VERSION 5.7 ;
  NOWIREEXTENSIONATPIN ON ;
  DIVIDERCHAR "/" ;
  BUSBITCHARS "[]" ;
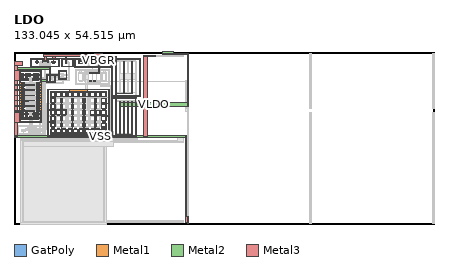
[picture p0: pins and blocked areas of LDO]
MACRO LDO
  CLASS BLOCK ;
  FOREIGN LDO ;
  ORIGIN -42.590 44.835 ;
  SIZE 133.045 BY 54.515 ;
  PIN VSS
    USE GROUND ;
    PORT
      LAYER GatPoly ;
        RECT 85.415 8.180 87.415 8.610 ;
        RECT 45.270 2.450 45.450 2.530 ;
        RECT 45.040 2.150 45.450 2.450 ;
        RECT 45.270 2.080 45.450 2.150 ;
        RECT 45.750 2.080 45.930 2.530 ;
        RECT 46.370 2.450 46.550 2.530 ;
        RECT 46.140 2.150 46.550 2.450 ;
        RECT 46.370 2.080 46.550 2.150 ;
        RECT 46.850 2.080 47.030 2.530 ;
        RECT 47.470 2.450 47.650 2.530 ;
        RECT 47.240 2.150 47.650 2.450 ;
        RECT 47.470 2.080 47.650 2.150 ;
        RECT 47.950 2.080 48.130 2.530 ;
        RECT 48.570 2.080 48.750 2.530 ;
        RECT 49.050 2.450 49.230 2.530 ;
        RECT 49.050 2.150 49.460 2.450 ;
        RECT 49.050 2.080 49.230 2.150 ;
        RECT 49.670 2.080 49.850 2.530 ;
        RECT 50.150 2.450 50.330 2.530 ;
        RECT 50.150 2.150 50.560 2.450 ;
        RECT 50.150 2.080 50.330 2.150 ;
        RECT 45.270 1.110 45.450 1.190 ;
        RECT 45.040 0.810 45.450 1.110 ;
        RECT 45.270 0.740 45.450 0.810 ;
        RECT 45.750 0.740 45.930 1.190 ;
        RECT 46.370 1.110 46.550 1.190 ;
        RECT 46.140 0.810 46.550 1.110 ;
        RECT 46.370 0.740 46.550 0.810 ;
        RECT 46.850 0.740 47.030 1.190 ;
        RECT 48.570 0.740 48.750 1.190 ;
        RECT 49.050 1.110 49.230 1.190 ;
        RECT 49.050 0.810 49.460 1.110 ;
        RECT 49.050 0.740 49.230 0.810 ;
        RECT 49.670 0.740 49.850 1.190 ;
        RECT 50.150 1.110 50.330 1.190 ;
        RECT 50.150 0.810 50.560 1.110 ;
        RECT 50.150 0.740 50.330 0.810 ;
        RECT 45.270 -0.220 45.450 -0.150 ;
        RECT 45.040 -0.520 45.450 -0.220 ;
        RECT 45.270 -0.600 45.450 -0.520 ;
        RECT 45.750 -0.600 45.930 -0.150 ;
        RECT 49.670 -0.600 49.850 -0.150 ;
        RECT 50.150 -0.220 50.330 -0.150 ;
        RECT 50.150 -0.520 50.560 -0.220 ;
        RECT 50.150 -0.600 50.330 -0.520 ;
        RECT 45.270 -1.050 45.450 -0.980 ;
        RECT 45.040 -1.350 45.450 -1.050 ;
        RECT 45.270 -1.430 45.450 -1.350 ;
        RECT 45.750 -1.430 45.930 -0.980 ;
        RECT 49.670 -1.430 49.850 -0.980 ;
        RECT 50.150 -1.050 50.330 -0.980 ;
        RECT 50.150 -1.350 50.560 -1.050 ;
        RECT 50.150 -1.430 50.330 -1.350 ;
        RECT 45.270 -1.885 45.450 -1.810 ;
        RECT 45.040 -2.185 45.450 -1.885 ;
        RECT 45.270 -2.260 45.450 -2.185 ;
        RECT 45.750 -2.260 45.930 -1.810 ;
        RECT 49.670 -2.260 49.850 -1.810 ;
        RECT 50.150 -1.885 50.330 -1.810 ;
        RECT 50.150 -2.185 50.560 -1.885 ;
        RECT 50.150 -2.260 50.330 -2.185 ;
        RECT 45.270 -2.720 45.450 -2.640 ;
        RECT 45.040 -3.020 45.450 -2.720 ;
        RECT 45.270 -3.090 45.450 -3.020 ;
        RECT 45.750 -3.090 45.930 -2.640 ;
        RECT 49.670 -3.090 49.850 -2.640 ;
        RECT 50.150 -2.720 50.330 -2.640 ;
        RECT 50.150 -3.020 50.560 -2.720 ;
        RECT 50.150 -3.090 50.330 -3.020 ;
        RECT 54.585 -3.040 55.225 -2.810 ;
        RECT 56.375 -3.040 57.015 -2.810 ;
        RECT 58.185 -3.040 58.825 -2.810 ;
        RECT 59.975 -3.040 60.615 -2.810 ;
        RECT 61.755 -3.040 62.395 -2.810 ;
        RECT 63.545 -3.040 64.185 -2.810 ;
        RECT 65.355 -3.040 65.995 -2.810 ;
        RECT 67.145 -3.040 67.785 -2.810 ;
        RECT 68.905 -3.040 69.545 -2.810 ;
        RECT 70.695 -3.040 71.335 -2.810 ;
        RECT 54.460 -3.220 55.360 -3.040 ;
        RECT 56.250 -3.220 57.150 -3.040 ;
        RECT 58.040 -3.220 58.940 -3.040 ;
        RECT 59.830 -3.220 60.730 -3.040 ;
        RECT 61.620 -3.220 62.520 -3.040 ;
        RECT 63.410 -3.220 64.310 -3.040 ;
        RECT 65.200 -3.220 66.100 -3.040 ;
        RECT 66.990 -3.220 67.890 -3.040 ;
        RECT 68.780 -3.220 69.680 -3.040 ;
        RECT 70.570 -3.220 71.470 -3.040 ;
        RECT 45.270 -3.550 45.450 -3.470 ;
        RECT 45.040 -3.850 45.450 -3.550 ;
        RECT 45.270 -3.920 45.450 -3.850 ;
        RECT 45.750 -3.920 45.930 -3.470 ;
        RECT 49.670 -3.920 49.850 -3.470 ;
        RECT 50.150 -3.550 50.330 -3.470 ;
        RECT 50.150 -3.850 50.560 -3.550 ;
        RECT 50.150 -3.920 50.330 -3.850 ;
        RECT 45.270 -4.385 45.450 -4.300 ;
        RECT 45.040 -4.685 45.450 -4.385 ;
        RECT 45.270 -4.750 45.450 -4.685 ;
        RECT 45.750 -4.750 45.930 -4.300 ;
        RECT 49.670 -4.750 49.850 -4.300 ;
        RECT 50.150 -4.385 50.330 -4.300 ;
        RECT 50.150 -4.685 50.560 -4.385 ;
        RECT 50.150 -4.750 50.330 -4.685 ;
        RECT 45.270 -5.215 45.450 -5.130 ;
        RECT 45.040 -5.515 45.450 -5.215 ;
        RECT 45.270 -5.580 45.450 -5.515 ;
        RECT 45.750 -5.580 45.930 -5.130 ;
        RECT 49.670 -5.580 49.850 -5.130 ;
        RECT 50.150 -5.215 50.330 -5.130 ;
        RECT 54.460 -5.150 55.360 -4.420 ;
        RECT 56.250 -4.600 57.150 -4.420 ;
        RECT 58.040 -4.600 58.940 -4.420 ;
        RECT 59.830 -4.600 60.730 -4.420 ;
        RECT 61.620 -4.600 62.520 -4.420 ;
        RECT 63.410 -4.600 64.310 -4.420 ;
        RECT 65.200 -4.600 66.100 -4.420 ;
        RECT 66.990 -4.600 67.890 -4.420 ;
        RECT 68.780 -4.600 69.680 -4.420 ;
        RECT 70.570 -4.600 71.470 -4.420 ;
        RECT 70.570 -5.150 71.470 -4.970 ;
        RECT 50.150 -5.515 50.560 -5.215 ;
        RECT 50.150 -5.580 50.330 -5.515 ;
        RECT 45.270 -6.030 45.450 -5.960 ;
        RECT 45.040 -6.330 45.450 -6.030 ;
        RECT 45.270 -6.410 45.450 -6.330 ;
        RECT 45.750 -6.410 45.930 -5.960 ;
        RECT 49.670 -6.410 49.850 -5.960 ;
        RECT 50.150 -6.030 50.330 -5.960 ;
        RECT 50.150 -6.330 50.560 -6.030 ;
        RECT 50.150 -6.410 50.330 -6.330 ;
        RECT 54.460 -6.530 55.360 -6.350 ;
        RECT 45.270 -6.860 45.450 -6.790 ;
        RECT 45.040 -7.160 45.450 -6.860 ;
        RECT 45.270 -7.240 45.450 -7.160 ;
        RECT 45.750 -7.240 45.930 -6.790 ;
        RECT 49.670 -7.240 49.850 -6.790 ;
        RECT 50.150 -6.860 50.330 -6.790 ;
        RECT 50.150 -7.160 50.560 -6.860 ;
        RECT 54.460 -7.080 55.360 -6.900 ;
        RECT 70.570 -7.080 71.470 -6.350 ;
        RECT 50.150 -7.240 50.330 -7.160 ;
        RECT 45.270 -7.695 45.450 -7.620 ;
        RECT 45.040 -7.995 45.450 -7.695 ;
        RECT 45.270 -8.070 45.450 -7.995 ;
        RECT 45.750 -8.070 45.930 -7.620 ;
        RECT 49.670 -8.070 49.850 -7.620 ;
        RECT 50.150 -7.695 50.330 -7.620 ;
        RECT 50.150 -7.995 50.560 -7.695 ;
        RECT 50.150 -8.070 50.330 -7.995 ;
        RECT 45.270 -8.525 45.450 -8.450 ;
        RECT 45.040 -8.825 45.450 -8.525 ;
        RECT 45.270 -8.900 45.450 -8.825 ;
        RECT 45.750 -8.900 45.930 -8.450 ;
        RECT 49.670 -8.900 49.850 -8.450 ;
        RECT 50.150 -8.525 50.330 -8.450 ;
        RECT 50.150 -8.825 50.560 -8.525 ;
        RECT 50.150 -8.900 50.330 -8.825 ;
        RECT 54.460 -9.010 55.360 -8.280 ;
        RECT 70.570 -8.460 71.470 -8.280 ;
        RECT 56.385 -8.830 57.025 -8.640 ;
        RECT 58.170 -8.830 58.810 -8.640 ;
        RECT 56.250 -9.010 57.150 -8.830 ;
        RECT 58.040 -9.010 58.940 -8.830 ;
        RECT 66.990 -9.010 67.890 -8.830 ;
        RECT 68.780 -9.010 69.680 -8.830 ;
        RECT 70.570 -9.010 71.470 -8.830 ;
        RECT 45.270 -9.865 45.450 -9.790 ;
        RECT 45.040 -10.165 45.450 -9.865 ;
        RECT 45.270 -10.240 45.450 -10.165 ;
        RECT 45.750 -10.240 45.930 -9.790 ;
        RECT 46.370 -9.870 46.550 -9.790 ;
        RECT 46.140 -10.170 46.550 -9.870 ;
        RECT 46.370 -10.240 46.550 -10.170 ;
        RECT 46.850 -10.240 47.030 -9.790 ;
        RECT 48.570 -10.240 48.750 -9.790 ;
        RECT 49.050 -9.870 49.230 -9.790 ;
        RECT 49.050 -10.170 49.460 -9.870 ;
        RECT 49.050 -10.240 49.230 -10.170 ;
        RECT 49.670 -10.240 49.850 -9.790 ;
        RECT 50.150 -9.865 50.330 -9.790 ;
        RECT 50.150 -10.165 50.560 -9.865 ;
        RECT 50.150 -10.240 50.330 -10.165 ;
        RECT 54.460 -10.390 55.360 -10.210 ;
        RECT 56.250 -10.390 57.150 -10.210 ;
        RECT 58.040 -10.390 58.940 -10.210 ;
        RECT 66.990 -10.390 67.890 -10.210 ;
        RECT 68.780 -10.390 69.680 -10.210 ;
        RECT 67.120 -10.580 67.760 -10.390 ;
        RECT 68.905 -10.580 69.545 -10.390 ;
        RECT 54.460 -10.940 55.360 -10.760 ;
        RECT 70.570 -10.940 71.470 -10.210 ;
        RECT 45.270 -11.210 45.450 -11.130 ;
        RECT 45.040 -11.510 45.450 -11.210 ;
        RECT 45.270 -11.580 45.450 -11.510 ;
        RECT 45.750 -11.580 45.930 -11.130 ;
        RECT 46.370 -11.210 46.550 -11.130 ;
        RECT 46.140 -11.510 46.550 -11.210 ;
        RECT 46.370 -11.580 46.550 -11.510 ;
        RECT 46.850 -11.580 47.030 -11.130 ;
        RECT 47.470 -11.580 47.650 -11.130 ;
        RECT 47.950 -11.210 48.130 -11.130 ;
        RECT 47.950 -11.510 48.360 -11.210 ;
        RECT 47.950 -11.580 48.130 -11.510 ;
        RECT 48.570 -11.580 48.750 -11.130 ;
        RECT 49.050 -11.210 49.230 -11.130 ;
        RECT 49.050 -11.510 49.460 -11.210 ;
        RECT 49.050 -11.580 49.230 -11.510 ;
        RECT 49.670 -11.580 49.850 -11.130 ;
        RECT 50.150 -11.205 50.330 -11.130 ;
        RECT 50.150 -11.505 50.560 -11.205 ;
        RECT 50.150 -11.580 50.330 -11.505 ;
        RECT 54.460 -12.870 55.360 -12.140 ;
        RECT 70.570 -12.320 71.470 -12.140 ;
        RECT 70.570 -12.870 71.470 -12.690 ;
        RECT 54.460 -14.250 55.360 -14.070 ;
        RECT 54.460 -14.800 55.360 -14.620 ;
        RECT 56.250 -14.800 57.150 -14.620 ;
        RECT 58.040 -14.800 58.940 -14.620 ;
        RECT 59.830 -14.800 60.730 -14.620 ;
        RECT 61.620 -14.800 62.520 -14.620 ;
        RECT 63.410 -14.800 64.310 -14.620 ;
        RECT 65.200 -14.800 66.100 -14.620 ;
        RECT 66.990 -14.800 67.890 -14.620 ;
        RECT 68.780 -14.800 69.680 -14.620 ;
        RECT 70.570 -14.800 71.470 -14.070 ;
        RECT 54.460 -16.180 55.360 -16.000 ;
        RECT 56.250 -16.180 57.150 -16.000 ;
        RECT 58.040 -16.180 58.940 -16.000 ;
        RECT 59.830 -16.180 60.730 -16.000 ;
        RECT 61.620 -16.180 62.520 -16.000 ;
        RECT 63.410 -16.180 64.310 -16.000 ;
        RECT 65.200 -16.180 66.100 -16.000 ;
        RECT 66.990 -16.180 67.890 -16.000 ;
        RECT 68.780 -16.180 69.680 -16.000 ;
        RECT 70.570 -16.180 71.470 -16.000 ;
        RECT 54.585 -16.410 55.225 -16.180 ;
        RECT 56.375 -16.410 57.015 -16.180 ;
        RECT 58.185 -16.410 58.825 -16.180 ;
        RECT 59.975 -16.410 60.615 -16.180 ;
        RECT 61.755 -16.410 62.395 -16.180 ;
        RECT 63.545 -16.410 64.185 -16.180 ;
        RECT 65.355 -16.410 65.995 -16.180 ;
        RECT 67.145 -16.410 67.785 -16.180 ;
        RECT 68.905 -16.410 69.545 -16.180 ;
        RECT 70.695 -16.410 71.335 -16.180 ;
        RECT 97.595 -44.525 98.025 -42.525 ;
      LAYER Metal1 ;
        RECT 83.660 8.310 87.395 8.610 ;
        RECT 44.350 3.425 51.250 3.725 ;
        RECT 44.350 2.430 44.650 3.425 ;
        RECT 45.110 2.640 45.750 2.800 ;
        RECT 46.210 2.640 46.850 2.800 ;
        RECT 47.310 2.640 47.950 2.800 ;
        RECT 48.750 2.640 49.390 2.800 ;
        RECT 49.850 2.640 50.490 2.800 ;
        RECT 45.110 2.430 45.270 2.640 ;
        RECT 46.210 2.430 46.370 2.640 ;
        RECT 47.310 2.430 47.470 2.640 ;
        RECT 44.350 2.170 47.470 2.430 ;
        RECT 44.350 1.090 44.650 2.170 ;
        RECT 45.110 1.970 45.270 2.170 ;
        RECT 46.210 1.970 46.370 2.170 ;
        RECT 47.310 1.970 47.470 2.170 ;
        RECT 49.230 2.430 49.390 2.640 ;
        RECT 50.330 2.430 50.490 2.640 ;
        RECT 50.950 2.430 51.250 3.425 ;
        RECT 56.730 3.420 59.370 3.720 ;
        RECT 49.230 2.170 51.250 2.430 ;
        RECT 49.230 1.970 49.390 2.170 ;
        RECT 50.330 1.970 50.490 2.170 ;
        RECT 45.110 1.810 45.750 1.970 ;
        RECT 46.210 1.810 46.850 1.970 ;
        RECT 47.310 1.810 47.950 1.970 ;
        RECT 48.750 1.810 49.390 1.970 ;
        RECT 49.850 1.810 50.490 1.970 ;
        RECT 45.110 1.300 45.750 1.460 ;
        RECT 46.210 1.300 46.850 1.460 ;
        RECT 48.750 1.300 49.390 1.460 ;
        RECT 49.850 1.300 50.490 1.460 ;
        RECT 45.110 1.090 45.270 1.300 ;
        RECT 46.210 1.090 46.370 1.300 ;
        RECT 44.350 0.830 46.370 1.090 ;
        RECT 44.350 0.120 44.650 0.830 ;
        RECT 45.110 0.630 45.270 0.830 ;
        RECT 46.210 0.630 46.370 0.830 ;
        RECT 49.230 1.090 49.390 1.300 ;
        RECT 50.330 1.090 50.490 1.300 ;
        RECT 50.950 1.090 51.250 2.170 ;
        RECT 49.230 0.830 51.250 1.090 ;
        RECT 49.230 0.630 49.390 0.830 ;
        RECT 50.330 0.630 50.490 0.830 ;
        RECT 45.110 0.470 45.750 0.630 ;
        RECT 46.210 0.470 46.850 0.630 ;
        RECT 48.750 0.470 49.390 0.630 ;
        RECT 49.850 0.470 50.490 0.630 ;
        RECT 50.950 0.120 51.250 0.830 ;
        RECT 44.350 -0.040 45.750 0.120 ;
        RECT 49.850 -0.040 51.250 0.120 ;
        RECT 52.960 2.275 55.810 2.575 ;
        RECT 52.960 0.375 53.260 2.275 ;
        RECT 53.890 1.470 54.050 1.475 ;
        RECT 53.840 0.770 54.050 1.470 ;
        RECT 55.510 0.375 55.810 2.275 ;
        RECT 56.730 1.180 57.030 3.420 ;
        RECT 59.070 1.180 59.370 3.420 ;
        RECT 56.730 0.880 59.370 1.180 ;
        RECT 52.960 0.075 55.810 0.375 ;
        RECT 44.350 -0.710 45.270 -0.040 ;
        RECT 46.350 -0.710 47.050 -0.680 ;
        RECT 50.330 -0.710 51.250 -0.040 ;
        RECT 44.350 -0.870 45.750 -0.710 ;
        RECT 46.350 -0.870 49.050 -0.710 ;
        RECT 49.850 -0.870 51.250 -0.710 ;
        RECT 44.350 -1.540 45.270 -0.870 ;
        RECT 46.350 -0.890 47.050 -0.870 ;
        RECT 50.330 -1.540 51.250 -0.870 ;
        RECT 44.350 -1.700 45.750 -1.540 ;
        RECT 49.850 -1.700 51.250 -1.540 ;
        RECT 44.350 -2.370 45.270 -1.700 ;
        RECT 46.350 -2.370 47.050 -2.345 ;
        RECT 50.330 -2.370 51.250 -1.700 ;
        RECT 44.350 -2.530 45.750 -2.370 ;
        RECT 46.350 -2.530 49.050 -2.370 ;
        RECT 49.850 -2.530 51.250 -2.370 ;
        RECT 44.350 -3.200 45.270 -2.530 ;
        RECT 46.350 -2.555 47.050 -2.530 ;
        RECT 50.330 -3.200 51.250 -2.530 ;
        RECT 44.350 -3.360 45.750 -3.200 ;
        RECT 49.850 -3.360 51.250 -3.200 ;
        RECT 44.350 -4.030 45.270 -3.360 ;
        RECT 46.350 -4.030 47.050 -4.005 ;
        RECT 50.330 -4.030 51.250 -3.360 ;
        RECT 44.350 -4.190 45.750 -4.030 ;
        RECT 46.350 -4.190 49.050 -4.030 ;
        RECT 49.850 -4.190 51.250 -4.030 ;
        RECT 44.350 -4.860 45.270 -4.190 ;
        RECT 46.350 -4.215 47.050 -4.190 ;
        RECT 50.330 -4.860 51.250 -4.190 ;
        RECT 44.350 -5.020 45.750 -4.860 ;
        RECT 49.850 -5.020 51.250 -4.860 ;
        RECT 44.350 -5.690 45.270 -5.020 ;
        RECT 46.350 -5.690 47.050 -5.665 ;
        RECT 50.330 -5.690 51.250 -5.020 ;
        RECT 44.350 -5.850 45.750 -5.690 ;
        RECT 46.350 -5.850 49.050 -5.690 ;
        RECT 49.850 -5.850 51.250 -5.690 ;
        RECT 44.350 -6.520 45.270 -5.850 ;
        RECT 46.350 -5.875 47.050 -5.850 ;
        RECT 50.330 -6.520 51.250 -5.850 ;
        RECT 44.350 -6.680 45.750 -6.520 ;
        RECT 49.850 -6.680 51.250 -6.520 ;
        RECT 44.350 -7.350 45.270 -6.680 ;
        RECT 46.350 -7.350 47.050 -7.325 ;
        RECT 50.330 -7.350 51.250 -6.680 ;
        RECT 44.350 -7.510 45.750 -7.350 ;
        RECT 46.350 -7.510 49.050 -7.350 ;
        RECT 49.850 -7.510 51.250 -7.350 ;
        RECT 44.350 -8.180 45.270 -7.510 ;
        RECT 46.350 -7.535 47.050 -7.510 ;
        RECT 50.330 -8.180 51.250 -7.510 ;
        RECT 44.350 -8.340 45.750 -8.180 ;
        RECT 49.850 -8.340 51.250 -8.180 ;
        RECT 44.350 -9.010 45.270 -8.340 ;
        RECT 46.345 -9.010 47.045 -8.985 ;
        RECT 50.330 -9.010 51.250 -8.340 ;
        RECT 44.350 -9.170 45.750 -9.010 ;
        RECT 46.345 -9.170 49.050 -9.010 ;
        RECT 49.850 -9.170 51.250 -9.010 ;
        RECT 44.350 -9.885 44.650 -9.170 ;
        RECT 46.345 -9.195 47.045 -9.170 ;
        RECT 45.110 -9.680 45.750 -9.520 ;
        RECT 46.210 -9.680 46.850 -9.520 ;
        RECT 48.750 -9.680 49.390 -9.520 ;
        RECT 49.850 -9.680 50.490 -9.520 ;
        RECT 45.110 -9.885 45.270 -9.680 ;
        RECT 44.350 -9.890 45.270 -9.885 ;
        RECT 46.210 -9.890 46.370 -9.680 ;
        RECT 44.350 -10.145 46.370 -9.890 ;
        RECT 44.350 -11.230 44.650 -10.145 ;
        RECT 45.110 -10.150 46.370 -10.145 ;
        RECT 45.110 -10.350 45.270 -10.150 ;
        RECT 46.210 -10.350 46.370 -10.150 ;
        RECT 49.230 -9.890 49.390 -9.680 ;
        RECT 50.330 -9.890 50.490 -9.680 ;
        RECT 50.950 -9.890 51.250 -9.170 ;
        RECT 49.230 -10.150 51.250 -9.890 ;
        RECT 49.230 -10.350 49.390 -10.150 ;
        RECT 50.330 -10.350 50.490 -10.150 ;
        RECT 45.110 -10.510 45.750 -10.350 ;
        RECT 46.210 -10.510 46.850 -10.350 ;
        RECT 48.750 -10.510 49.390 -10.350 ;
        RECT 49.850 -10.510 50.490 -10.350 ;
        RECT 45.110 -11.020 45.750 -10.860 ;
        RECT 46.210 -11.020 46.850 -10.860 ;
        RECT 47.650 -11.020 48.290 -10.860 ;
        RECT 48.750 -11.020 49.390 -10.860 ;
        RECT 49.850 -11.020 50.490 -10.860 ;
        RECT 45.110 -11.230 45.270 -11.020 ;
        RECT 46.210 -11.230 46.370 -11.020 ;
        RECT 44.350 -11.490 46.370 -11.230 ;
        RECT 44.350 -12.475 44.650 -11.490 ;
        RECT 45.110 -11.690 45.270 -11.490 ;
        RECT 46.210 -11.690 46.370 -11.490 ;
        RECT 48.130 -11.230 48.290 -11.020 ;
        RECT 49.230 -11.230 49.390 -11.020 ;
        RECT 50.330 -11.230 50.490 -11.020 ;
        RECT 50.950 -11.230 51.250 -10.150 ;
        RECT 48.130 -11.490 51.250 -11.230 ;
        RECT 48.130 -11.690 48.290 -11.490 ;
        RECT 49.230 -11.690 49.390 -11.490 ;
        RECT 50.330 -11.690 50.490 -11.490 ;
        RECT 45.110 -11.850 45.750 -11.690 ;
        RECT 46.210 -11.850 46.850 -11.690 ;
        RECT 47.650 -11.850 48.290 -11.690 ;
        RECT 48.750 -11.850 49.390 -11.690 ;
        RECT 49.850 -11.850 50.490 -11.690 ;
        RECT 50.950 -12.475 51.250 -11.490 ;
        RECT 44.350 -12.775 51.250 -12.475 ;
        RECT 53.215 -2.385 72.715 -2.085 ;
        RECT 53.215 -8.565 53.515 -2.385 ;
        RECT 60.045 -2.880 65.975 -2.385 ;
        RECT 54.190 -3.040 71.740 -2.880 ;
        RECT 54.190 -4.705 54.350 -3.040 ;
        RECT 55.470 -4.705 55.630 -3.040 ;
        RECT 55.980 -4.420 56.140 -3.040 ;
        RECT 57.260 -4.420 57.420 -3.040 ;
        RECT 57.770 -4.420 57.930 -3.040 ;
        RECT 59.050 -4.420 59.210 -3.040 ;
        RECT 59.560 -4.420 59.720 -3.040 ;
        RECT 60.840 -4.420 61.000 -3.040 ;
        RECT 61.350 -4.420 61.510 -3.040 ;
        RECT 62.630 -4.420 62.790 -3.040 ;
        RECT 63.140 -4.420 63.300 -3.040 ;
        RECT 64.420 -4.420 64.580 -3.040 ;
        RECT 64.930 -4.420 65.090 -3.040 ;
        RECT 66.210 -4.420 66.370 -3.040 ;
        RECT 66.720 -4.420 66.880 -3.040 ;
        RECT 68.000 -4.420 68.160 -3.040 ;
        RECT 68.510 -4.420 68.670 -3.040 ;
        RECT 69.790 -4.420 69.950 -3.040 ;
        RECT 70.300 -4.420 70.460 -3.040 ;
        RECT 71.580 -4.420 71.740 -3.040 ;
        RECT 54.190 -4.865 55.630 -4.705 ;
        RECT 54.190 -6.350 54.350 -4.865 ;
        RECT 55.470 -6.350 55.630 -4.865 ;
        RECT 57.260 -6.350 57.930 -5.150 ;
        RECT 60.840 -6.350 61.510 -5.150 ;
        RECT 64.420 -6.350 65.090 -5.150 ;
        RECT 68.000 -6.350 68.670 -5.150 ;
        RECT 70.300 -6.635 70.460 -5.150 ;
        RECT 71.580 -6.635 71.740 -5.150 ;
        RECT 72.415 -6.635 72.715 -2.385 ;
        RECT 70.300 -6.795 72.715 -6.635 ;
        RECT 54.190 -8.565 54.350 -7.080 ;
        RECT 55.470 -8.565 55.630 -7.080 ;
        RECT 57.260 -8.280 57.930 -7.080 ;
        RECT 60.840 -8.280 61.510 -7.080 ;
        RECT 64.420 -8.280 65.090 -7.080 ;
        RECT 68.000 -8.280 68.670 -7.080 ;
        RECT 70.300 -8.280 70.460 -6.795 ;
        RECT 71.580 -8.280 71.740 -6.795 ;
        RECT 53.215 -8.710 55.630 -8.565 ;
        RECT 53.215 -8.725 59.210 -8.710 ;
        RECT 53.215 -12.425 53.515 -8.725 ;
        RECT 54.190 -10.210 54.350 -8.725 ;
        RECT 55.470 -8.870 59.210 -8.725 ;
        RECT 55.470 -10.210 55.630 -8.870 ;
        RECT 55.980 -10.210 56.140 -8.870 ;
        RECT 57.260 -10.210 57.420 -8.870 ;
        RECT 57.770 -10.210 57.930 -8.870 ;
        RECT 59.050 -10.210 59.210 -8.870 ;
        RECT 60.840 -10.210 61.510 -9.010 ;
        RECT 64.420 -10.210 65.090 -9.010 ;
        RECT 66.720 -10.350 66.880 -9.010 ;
        RECT 68.000 -10.350 68.160 -9.010 ;
        RECT 68.510 -10.350 68.670 -9.010 ;
        RECT 69.790 -10.350 69.950 -9.010 ;
        RECT 70.300 -10.350 70.460 -9.010 ;
        RECT 66.720 -10.495 70.460 -10.350 ;
        RECT 71.580 -10.495 71.740 -9.010 ;
        RECT 72.415 -10.495 72.715 -6.795 ;
        RECT 66.720 -10.510 72.715 -10.495 ;
        RECT 70.300 -10.655 72.715 -10.510 ;
        RECT 54.190 -12.425 54.350 -10.940 ;
        RECT 55.470 -12.425 55.630 -10.940 ;
        RECT 57.260 -12.140 57.930 -10.940 ;
        RECT 60.840 -12.140 61.510 -10.940 ;
        RECT 64.420 -12.140 65.090 -10.940 ;
        RECT 68.000 -12.140 68.670 -10.940 ;
        RECT 70.300 -12.140 70.460 -10.655 ;
        RECT 71.580 -12.140 71.740 -10.655 ;
        RECT 53.215 -12.585 55.630 -12.425 ;
        RECT 53.215 -16.835 53.515 -12.585 ;
        RECT 54.190 -14.070 54.350 -12.585 ;
        RECT 55.470 -14.070 55.630 -12.585 ;
        RECT 57.260 -14.070 57.930 -12.870 ;
        RECT 60.840 -14.070 61.510 -12.870 ;
        RECT 64.420 -14.070 65.090 -12.870 ;
        RECT 68.000 -14.070 68.670 -12.870 ;
        RECT 70.300 -14.355 70.460 -12.870 ;
        RECT 71.580 -14.355 71.740 -12.870 ;
        RECT 70.300 -14.515 71.740 -14.355 ;
        RECT 54.190 -16.180 54.350 -14.800 ;
        RECT 55.470 -16.180 55.630 -14.800 ;
        RECT 55.980 -16.180 56.140 -14.800 ;
        RECT 57.260 -16.180 57.420 -14.800 ;
        RECT 57.770 -16.180 57.930 -14.800 ;
        RECT 59.050 -16.180 59.210 -14.800 ;
        RECT 59.560 -16.180 59.720 -14.800 ;
        RECT 60.840 -16.180 61.000 -14.800 ;
        RECT 61.350 -16.180 61.510 -14.800 ;
        RECT 62.630 -16.180 62.790 -14.800 ;
        RECT 63.140 -16.180 63.300 -14.800 ;
        RECT 64.420 -16.180 64.580 -14.800 ;
        RECT 64.930 -16.180 65.090 -14.800 ;
        RECT 66.210 -16.180 66.370 -14.800 ;
        RECT 66.720 -16.180 66.880 -14.800 ;
        RECT 68.000 -16.180 68.160 -14.800 ;
        RECT 68.510 -16.180 68.670 -14.800 ;
        RECT 69.790 -16.180 69.950 -14.800 ;
        RECT 70.300 -16.180 70.460 -14.515 ;
        RECT 71.580 -16.180 71.740 -14.515 ;
        RECT 54.190 -16.340 71.740 -16.180 ;
        RECT 57.245 -16.835 57.945 -16.790 ;
        RECT 60.045 -16.835 65.975 -16.340 ;
        RECT 67.985 -16.835 68.685 -16.790 ;
        RECT 72.415 -16.835 72.715 -10.655 ;
        RECT 53.215 -17.135 72.715 -16.835 ;
        RECT 57.245 -17.410 57.945 -17.135 ;
        RECT 60.825 -17.410 61.525 -17.135 ;
        RECT 64.405 -17.410 65.105 -17.135 ;
        RECT 67.985 -17.410 68.685 -17.135 ;
        RECT 97.595 -44.505 97.895 -42.545 ;
      LAYER Metal2 ;
        RECT 83.660 8.365 84.770 8.565 ;
        RECT 43.065 4.000 54.045 4.700 ;
        RECT 44.395 0.495 44.595 3.655 ;
        RECT 55.515 2.210 57.025 2.410 ;
        RECT 51.000 0.260 53.210 0.960 ;
        RECT 53.840 0.770 54.050 1.470 ;
        RECT 46.350 -0.890 47.050 -0.680 ;
        RECT 46.350 -2.555 47.050 -2.345 ;
        RECT 46.350 -4.215 47.050 -4.005 ;
        RECT 46.350 -5.875 47.050 -5.665 ;
        RECT 57.495 -6.305 57.695 -5.195 ;
        RECT 61.075 -6.305 61.275 -5.195 ;
        RECT 64.655 -6.305 64.855 -5.195 ;
        RECT 68.235 -6.305 68.435 -5.195 ;
        RECT 46.350 -7.535 47.050 -7.325 ;
        RECT 57.495 -8.230 57.695 -7.120 ;
        RECT 61.075 -8.230 61.275 -7.120 ;
        RECT 64.655 -8.230 64.855 -7.120 ;
        RECT 68.235 -8.230 68.435 -7.120 ;
        RECT 46.345 -9.195 47.045 -8.985 ;
        RECT 44.395 -12.705 44.595 -9.545 ;
        RECT 61.075 -10.175 61.275 -9.065 ;
        RECT 64.655 -10.175 64.855 -9.065 ;
        RECT 57.495 -12.105 57.695 -10.995 ;
        RECT 61.075 -12.105 61.275 -10.995 ;
        RECT 64.655 -12.105 64.855 -10.995 ;
        RECT 68.235 -12.105 68.435 -10.995 ;
        RECT 57.495 -14.010 57.695 -12.900 ;
        RECT 61.075 -14.010 61.275 -12.900 ;
        RECT 64.655 -14.010 64.855 -12.900 ;
        RECT 68.235 -14.010 68.435 -12.900 ;
        RECT 97.055 -16.795 97.255 -16.740 ;
        RECT 42.850 -17.405 97.255 -16.795 ;
        RECT 97.055 -17.440 97.255 -17.405 ;
        RECT 97.640 -44.490 97.840 -42.560 ;
      LAYER Metal3 ;
        RECT 42.590 5.390 45.300 6.740 ;
        RECT 42.590 3.655 43.545 5.390 ;
        RECT 42.590 0.495 44.595 3.655 ;
        RECT 53.845 0.770 54.045 4.700 ;
        RECT 42.590 -0.550 43.545 0.495 ;
        RECT 42.590 -1.055 47.050 -0.550 ;
        RECT 42.590 -2.350 43.545 -1.055 ;
        RECT 42.590 -2.550 47.050 -2.350 ;
        RECT 42.590 -4.010 43.545 -2.550 ;
        RECT 42.590 -4.210 47.050 -4.010 ;
        RECT 42.590 -5.670 43.545 -4.210 ;
        RECT 42.590 -5.870 47.050 -5.670 ;
        RECT 42.590 -7.330 43.545 -5.870 ;
        RECT 42.590 -7.530 47.050 -7.330 ;
        RECT 42.590 -8.990 43.545 -7.530 ;
        RECT 42.590 -9.190 47.045 -8.990 ;
        RECT 42.590 -9.545 43.545 -9.190 ;
        RECT 42.590 -12.705 44.595 -9.545 ;
        RECT 42.590 -16.795 43.545 -12.705 ;
        RECT 57.495 -16.795 57.695 -5.195 ;
        RECT 61.075 -16.795 61.275 -5.195 ;
        RECT 64.655 -16.795 64.855 -5.195 ;
        RECT 68.235 -16.795 68.435 -5.195 ;
        RECT 42.590 -17.200 43.550 -16.795 ;
        RECT 42.850 -17.405 43.550 -17.200 ;
        RECT 57.245 -17.405 57.945 -16.795 ;
        RECT 60.825 -17.405 61.525 -16.795 ;
        RECT 64.405 -17.405 65.105 -16.795 ;
        RECT 67.985 -17.405 68.685 -16.795 ;
        RECT 83.660 -17.200 84.770 8.610 ;
        RECT 97.030 -42.560 97.280 -16.740 ;
        RECT 97.030 -44.490 97.840 -42.560 ;
    END
  END VSS
  PIN VBGR
    ANTENNAGATEAREA 4.050000 ;
    PORT
      LAYER GatPoly ;
        RECT 66.485 2.940 67.125 3.170 ;
        RECT 67.770 2.940 68.410 3.170 ;
        RECT 66.360 2.760 67.260 2.940 ;
        RECT 67.640 2.760 68.540 2.940 ;
        RECT 66.360 0.330 67.260 0.510 ;
        RECT 67.640 0.330 68.540 0.510 ;
      LAYER Metal1 ;
        RECT 66.455 2.915 67.155 3.125 ;
        RECT 67.740 2.915 68.440 3.125 ;
      LAYER Metal2 ;
        RECT 66.455 2.920 69.705 3.120 ;
      LAYER Metal3 ;
        RECT 68.230 8.240 70.660 9.075 ;
        RECT 69.415 2.920 69.705 8.240 ;
    END
  END VBGR
  PIN VDD
    USE POWER ;
    PORT
      LAYER GatPoly ;
        RECT 49.725 6.560 50.025 6.790 ;
        RECT 54.945 6.560 55.245 6.790 ;
        RECT 63.435 6.665 64.075 6.965 ;
        RECT 70.855 6.665 71.495 6.965 ;
        RECT 49.675 6.380 50.075 6.560 ;
        RECT 54.895 6.380 55.295 6.560 ;
        RECT 63.300 6.485 64.200 6.665 ;
        RECT 70.720 6.485 71.620 6.665 ;
        RECT 49.675 6.050 50.075 6.230 ;
        RECT 54.895 6.050 55.295 6.230 ;
        RECT 63.300 5.855 64.200 6.035 ;
        RECT 70.720 5.855 71.620 6.035 ;
      LAYER Metal1 ;
        RECT 47.885 7.405 57.085 7.705 ;
        RECT 47.885 5.205 48.185 7.405 ;
        RECT 49.745 6.720 50.005 7.405 ;
        RECT 52.135 6.835 52.835 6.905 ;
        RECT 49.375 6.560 50.375 6.720 ;
        RECT 49.375 6.175 49.535 6.560 ;
        RECT 50.215 6.175 50.375 6.560 ;
        RECT 51.565 6.675 53.405 6.835 ;
        RECT 54.965 6.720 55.225 7.405 ;
        RECT 51.565 6.175 51.725 6.675 ;
        RECT 53.245 6.175 53.405 6.675 ;
        RECT 54.595 6.560 55.595 6.720 ;
        RECT 54.595 6.175 54.755 6.560 ;
        RECT 55.435 6.175 55.595 6.560 ;
        RECT 56.785 5.205 57.085 7.405 ;
        RECT 47.885 4.905 57.085 5.205 ;
        RECT 57.785 7.405 61.285 7.705 ;
        RECT 57.785 5.205 58.085 7.405 ;
        RECT 59.015 6.155 59.225 6.855 ;
        RECT 60.985 5.205 61.285 7.405 ;
        RECT 57.785 4.905 61.285 5.205 ;
        RECT 61.710 7.400 73.210 7.700 ;
        RECT 61.710 5.000 62.010 7.400 ;
        RECT 63.455 6.895 64.055 7.400 ;
        RECT 67.155 6.930 67.855 7.110 ;
        RECT 63.030 6.735 64.470 6.895 ;
        RECT 63.030 6.035 63.190 6.735 ;
        RECT 64.310 6.035 64.470 6.735 ;
        RECT 66.100 6.770 68.820 6.930 ;
        RECT 70.875 6.895 71.475 7.400 ;
        RECT 66.100 6.035 66.260 6.770 ;
        RECT 68.660 6.035 68.820 6.770 ;
        RECT 70.450 6.735 71.890 6.895 ;
        RECT 70.450 6.035 70.610 6.735 ;
        RECT 71.730 6.035 71.890 6.735 ;
        RECT 72.910 5.000 73.210 7.400 ;
        RECT 61.710 4.700 73.210 5.000 ;
        RECT 73.565 7.405 82.665 7.705 ;
        RECT 73.565 -3.995 73.865 7.405 ;
        RECT 74.835 5.445 74.995 6.505 ;
        RECT 74.810 3.515 75.020 5.445 ;
        RECT 74.835 -3.345 74.995 3.515 ;
        RECT 77.395 -3.345 77.555 6.505 ;
        RECT 79.955 -3.345 80.115 6.505 ;
        RECT 74.835 -3.505 80.115 -3.345 ;
        RECT 82.365 -3.995 82.665 7.405 ;
        RECT 73.565 -4.295 82.665 -3.995 ;
        RECT 73.565 -4.900 73.865 -4.295 ;
        RECT 73.565 -5.200 81.365 -4.900 ;
        RECT 73.565 -17.050 73.865 -5.200 ;
        RECT 74.825 -9.040 74.985 -6.150 ;
        RECT 74.810 -10.560 75.020 -9.040 ;
        RECT 74.825 -16.375 74.985 -10.560 ;
        RECT 77.385 -16.375 77.545 -6.150 ;
        RECT 79.945 -16.375 80.105 -6.150 ;
        RECT 74.825 -16.535 80.105 -16.375 ;
        RECT 81.065 -17.050 81.365 -5.200 ;
        RECT 73.565 -17.350 81.365 -17.050 ;
      LAYER Metal2 ;
        RECT 67.150 8.325 67.850 8.330 ;
        RECT 67.150 8.125 67.855 8.325 ;
        RECT 67.150 7.915 75.055 8.125 ;
        RECT 54.895 7.650 55.595 7.655 ;
        RECT 54.895 7.450 77.865 7.650 ;
        RECT 52.135 6.695 52.835 6.905 ;
        RECT 67.155 6.900 67.855 7.110 ;
        RECT 59.015 6.155 59.225 6.855 ;
        RECT 74.815 3.515 75.015 5.445 ;
        RECT 74.815 -10.560 75.015 -9.040 ;
      LAYER Metal3 ;
        RECT 51.925 8.325 67.850 8.830 ;
        RECT 51.925 8.140 67.855 8.325 ;
        RECT 52.135 6.695 52.835 8.140 ;
        RECT 54.895 7.450 55.595 8.140 ;
        RECT 59.020 6.155 59.220 8.140 ;
        RECT 67.150 8.125 67.855 8.140 ;
        RECT 67.150 7.105 67.850 8.125 ;
        RECT 74.765 7.920 75.055 8.120 ;
        RECT 67.150 6.905 67.855 7.105 ;
        RECT 67.150 6.830 67.850 6.905 ;
        RECT 74.815 -10.560 75.015 7.920 ;
    END
  END VDD
  PIN VLDO
    ANTENNADIFFAREA 7.600000 ;
    PORT
      LAYER GatPoly ;
        RECT 97.595 7.295 98.025 9.295 ;
      LAYER Metal1 ;
        RECT 97.595 7.315 97.895 9.275 ;
        RECT 76.105 -6.200 76.265 -6.150 ;
        RECT 78.665 -6.200 78.825 -6.150 ;
        RECT 76.080 -7.720 76.290 -6.200 ;
        RECT 78.640 -7.720 78.850 -6.200 ;
        RECT 76.105 -16.150 76.265 -7.720 ;
        RECT 78.665 -16.150 78.825 -7.720 ;
      LAYER Metal2 ;
        RECT 89.740 9.255 93.130 9.680 ;
        RECT 89.740 8.990 97.845 9.255 ;
        RECT 97.645 7.325 97.845 8.990 ;
        RECT 76.085 -7.720 97.845 -6.200 ;
      LAYER Metal3 ;
        RECT 97.645 -7.720 97.845 9.255 ;
    END
  END VLDO
  OBS
      LAYER GatPoly ;
        RECT 87.615 8.180 89.615 8.610 ;
        RECT 89.815 8.180 91.815 8.610 ;
        RECT 92.015 8.180 94.015 8.610 ;
        RECT 94.215 8.180 96.215 8.610 ;
        RECT 136.335 7.295 136.895 9.295 ;
        RECT 175.205 7.295 175.635 9.295 ;
        RECT 59.385 6.635 59.685 6.865 ;
        RECT 75.250 6.685 75.890 6.985 ;
        RECT 76.530 6.685 77.170 6.985 ;
        RECT 77.800 6.685 78.440 6.985 ;
        RECT 79.085 6.685 79.725 6.985 ;
        RECT 80.355 6.685 80.995 6.985 ;
        RECT 51.025 6.380 51.425 6.560 ;
        RECT 51.865 6.380 52.265 6.560 ;
        RECT 52.705 6.380 53.105 6.560 ;
        RECT 53.545 6.380 53.945 6.560 ;
        RECT 59.335 6.455 59.735 6.635 ;
        RECT 65.090 6.485 65.990 6.665 ;
        RECT 66.370 6.485 67.270 6.665 ;
        RECT 67.650 6.485 68.550 6.665 ;
        RECT 68.930 6.485 69.830 6.665 ;
        RECT 75.105 6.505 76.005 6.685 ;
        RECT 76.385 6.505 77.285 6.685 ;
        RECT 77.665 6.505 78.565 6.685 ;
        RECT 78.945 6.505 79.845 6.685 ;
        RECT 80.225 6.505 81.125 6.685 ;
        RECT 51.025 6.050 51.425 6.230 ;
        RECT 51.865 6.050 52.265 6.230 ;
        RECT 52.705 6.050 53.105 6.230 ;
        RECT 53.545 6.050 53.945 6.230 ;
        RECT 51.075 5.765 51.375 6.050 ;
        RECT 51.915 5.765 52.215 6.050 ;
        RECT 52.755 5.765 53.055 6.050 ;
        RECT 53.595 5.765 53.895 6.050 ;
        RECT 59.335 5.975 59.735 6.155 ;
        RECT 65.090 5.855 65.990 6.035 ;
        RECT 66.370 5.855 67.270 6.035 ;
        RECT 67.650 5.855 68.550 6.035 ;
        RECT 68.930 5.855 69.830 6.035 ;
        RECT 65.225 5.555 65.865 5.855 ;
        RECT 66.500 5.555 67.140 5.855 ;
        RECT 67.770 5.555 68.410 5.855 ;
        RECT 69.045 5.555 69.685 5.855 ;
        RECT 97.595 5.095 98.025 7.095 ;
        RECT 136.335 5.095 136.895 7.095 ;
        RECT 175.205 5.095 175.635 7.095 ;
        RECT 63.420 2.940 64.060 3.170 ;
        RECT 70.840 2.940 71.480 3.170 ;
        RECT 63.290 2.760 64.190 2.940 ;
        RECT 65.080 2.760 65.980 2.940 ;
        RECT 68.920 2.760 69.820 2.940 ;
        RECT 70.710 2.760 71.610 2.940 ;
        RECT 97.595 2.895 98.025 4.895 ;
        RECT 136.335 2.895 136.895 4.895 ;
        RECT 175.205 2.895 175.635 4.895 ;
        RECT 57.795 2.075 57.975 2.525 ;
        RECT 58.275 2.455 58.455 2.525 ;
        RECT 58.275 2.155 58.755 2.455 ;
        RECT 58.275 2.075 58.455 2.155 ;
        RECT 54.245 1.710 54.545 2.010 ;
        RECT 54.160 1.475 54.610 1.710 ;
        RECT 47.470 0.740 47.650 1.190 ;
        RECT 47.950 1.120 48.130 1.190 ;
        RECT 47.950 0.820 48.360 1.120 ;
        RECT 54.160 0.995 54.610 1.175 ;
        RECT 47.950 0.740 48.130 0.820 ;
        RECT 97.595 0.695 98.025 2.695 ;
        RECT 136.335 0.695 136.895 2.695 ;
        RECT 175.205 0.695 175.635 2.695 ;
        RECT 63.290 0.330 64.190 0.510 ;
        RECT 65.080 0.330 65.980 0.510 ;
        RECT 68.920 0.330 69.820 0.510 ;
        RECT 70.710 0.330 71.610 0.510 ;
        RECT 65.210 0.100 65.850 0.330 ;
        RECT 69.050 0.100 69.690 0.330 ;
        RECT 46.370 -0.600 46.550 -0.150 ;
        RECT 46.850 -0.220 47.030 -0.150 ;
        RECT 46.850 -0.520 47.260 -0.220 ;
        RECT 46.850 -0.600 47.030 -0.520 ;
        RECT 47.470 -0.600 47.650 -0.150 ;
        RECT 47.950 -0.220 48.130 -0.150 ;
        RECT 47.950 -0.520 48.360 -0.220 ;
        RECT 47.950 -0.600 48.130 -0.520 ;
        RECT 48.570 -0.600 48.750 -0.150 ;
        RECT 49.050 -0.220 49.230 -0.150 ;
        RECT 49.050 -0.520 49.460 -0.220 ;
        RECT 49.050 -0.600 49.230 -0.520 ;
        RECT 46.370 -1.430 46.550 -0.980 ;
        RECT 46.850 -1.050 47.030 -0.980 ;
        RECT 46.850 -1.350 47.260 -1.050 ;
        RECT 46.850 -1.430 47.030 -1.350 ;
        RECT 47.470 -1.430 47.650 -0.980 ;
        RECT 47.950 -1.050 48.130 -0.980 ;
        RECT 47.950 -1.350 48.360 -1.050 ;
        RECT 47.950 -1.430 48.130 -1.350 ;
        RECT 48.570 -1.430 48.750 -0.980 ;
        RECT 49.050 -1.050 49.230 -0.980 ;
        RECT 49.050 -1.350 49.460 -1.050 ;
        RECT 49.050 -1.430 49.230 -1.350 ;
        RECT 97.595 -1.505 98.025 0.495 ;
        RECT 136.335 -1.505 136.895 0.495 ;
        RECT 175.205 -1.505 175.635 0.495 ;
        RECT 46.370 -2.260 46.550 -1.810 ;
        RECT 46.850 -1.885 47.030 -1.810 ;
        RECT 46.850 -2.185 47.260 -1.885 ;
        RECT 46.850 -2.260 47.030 -2.185 ;
        RECT 47.470 -2.260 47.650 -1.810 ;
        RECT 47.950 -1.885 48.130 -1.810 ;
        RECT 47.950 -2.185 48.360 -1.885 ;
        RECT 47.950 -2.260 48.130 -2.185 ;
        RECT 48.570 -2.260 48.750 -1.810 ;
        RECT 49.050 -1.885 49.230 -1.810 ;
        RECT 49.050 -2.185 49.460 -1.885 ;
        RECT 49.050 -2.260 49.230 -2.185 ;
        RECT 46.370 -3.090 46.550 -2.640 ;
        RECT 46.850 -2.720 47.030 -2.640 ;
        RECT 46.850 -3.020 47.260 -2.720 ;
        RECT 46.850 -3.090 47.030 -3.020 ;
        RECT 47.470 -3.090 47.650 -2.640 ;
        RECT 47.950 -2.720 48.130 -2.640 ;
        RECT 47.950 -3.020 48.360 -2.720 ;
        RECT 47.950 -3.090 48.130 -3.020 ;
        RECT 48.570 -3.090 48.750 -2.640 ;
        RECT 49.050 -2.720 49.230 -2.640 ;
        RECT 49.050 -3.020 49.460 -2.720 ;
        RECT 49.050 -3.090 49.230 -3.020 ;
        RECT 75.105 -3.275 76.005 -3.095 ;
        RECT 76.385 -3.275 77.285 -3.095 ;
        RECT 77.665 -3.275 78.565 -3.095 ;
        RECT 78.945 -3.275 79.845 -3.095 ;
        RECT 80.225 -3.275 81.125 -3.095 ;
        RECT 46.370 -3.920 46.550 -3.470 ;
        RECT 46.850 -3.545 47.030 -3.470 ;
        RECT 46.850 -3.845 47.260 -3.545 ;
        RECT 46.850 -3.920 47.030 -3.845 ;
        RECT 47.470 -3.920 47.650 -3.470 ;
        RECT 47.950 -3.545 48.130 -3.470 ;
        RECT 47.950 -3.845 48.360 -3.545 ;
        RECT 47.950 -3.920 48.130 -3.845 ;
        RECT 48.570 -3.920 48.750 -3.470 ;
        RECT 49.050 -3.545 49.230 -3.470 ;
        RECT 49.050 -3.845 49.460 -3.545 ;
        RECT 97.595 -3.705 98.025 -1.705 ;
        RECT 136.335 -3.705 136.895 -1.705 ;
        RECT 175.205 -3.705 175.635 -1.705 ;
        RECT 49.050 -3.920 49.230 -3.845 ;
        RECT 46.370 -4.750 46.550 -4.300 ;
        RECT 46.850 -4.385 47.030 -4.300 ;
        RECT 46.850 -4.685 47.260 -4.385 ;
        RECT 46.850 -4.750 47.030 -4.685 ;
        RECT 47.470 -4.750 47.650 -4.300 ;
        RECT 47.950 -4.385 48.130 -4.300 ;
        RECT 47.950 -4.685 48.360 -4.385 ;
        RECT 47.950 -4.750 48.130 -4.685 ;
        RECT 48.570 -4.750 48.750 -4.300 ;
        RECT 49.050 -4.385 49.230 -4.300 ;
        RECT 49.050 -4.685 49.460 -4.385 ;
        RECT 49.050 -4.750 49.230 -4.685 ;
        RECT 46.370 -5.580 46.550 -5.130 ;
        RECT 46.850 -5.205 47.030 -5.130 ;
        RECT 46.850 -5.505 47.260 -5.205 ;
        RECT 46.850 -5.580 47.030 -5.505 ;
        RECT 47.470 -5.580 47.650 -5.130 ;
        RECT 47.950 -5.205 48.130 -5.130 ;
        RECT 47.950 -5.505 48.360 -5.205 ;
        RECT 47.950 -5.580 48.130 -5.505 ;
        RECT 48.570 -5.580 48.750 -5.130 ;
        RECT 49.050 -5.205 49.230 -5.130 ;
        RECT 56.250 -5.150 57.150 -4.970 ;
        RECT 58.040 -5.150 58.940 -4.970 ;
        RECT 59.830 -5.150 60.730 -4.970 ;
        RECT 61.620 -5.150 62.520 -4.970 ;
        RECT 63.410 -5.150 64.310 -4.970 ;
        RECT 65.200 -5.150 66.100 -4.970 ;
        RECT 66.990 -5.150 67.890 -4.970 ;
        RECT 68.780 -5.150 69.680 -4.970 ;
        RECT 49.050 -5.505 49.460 -5.205 ;
        RECT 49.050 -5.580 49.230 -5.505 ;
        RECT 46.370 -6.410 46.550 -5.960 ;
        RECT 46.850 -6.035 47.030 -5.960 ;
        RECT 46.850 -6.335 47.260 -6.035 ;
        RECT 46.850 -6.410 47.030 -6.335 ;
        RECT 47.470 -6.410 47.650 -5.960 ;
        RECT 47.950 -6.035 48.130 -5.960 ;
        RECT 47.950 -6.335 48.360 -6.035 ;
        RECT 47.950 -6.410 48.130 -6.335 ;
        RECT 48.570 -6.410 48.750 -5.960 ;
        RECT 49.050 -6.035 49.230 -5.960 ;
        RECT 75.220 -5.970 75.860 -5.670 ;
        RECT 76.490 -5.970 77.130 -5.670 ;
        RECT 77.775 -5.970 78.415 -5.670 ;
        RECT 79.045 -5.970 79.685 -5.670 ;
        RECT 97.595 -5.905 98.025 -3.905 ;
        RECT 136.335 -5.905 136.895 -3.905 ;
        RECT 175.205 -5.905 175.635 -3.905 ;
        RECT 49.050 -6.335 49.460 -6.035 ;
        RECT 75.095 -6.150 75.995 -5.970 ;
        RECT 76.375 -6.150 77.275 -5.970 ;
        RECT 77.655 -6.150 78.555 -5.970 ;
        RECT 78.935 -6.150 79.835 -5.970 ;
        RECT 49.050 -6.410 49.230 -6.335 ;
        RECT 56.250 -6.530 57.150 -6.350 ;
        RECT 58.040 -6.530 58.940 -6.350 ;
        RECT 59.830 -6.530 60.730 -6.350 ;
        RECT 61.620 -6.530 62.520 -6.350 ;
        RECT 63.410 -6.530 64.310 -6.350 ;
        RECT 65.200 -6.530 66.100 -6.350 ;
        RECT 66.990 -6.530 67.890 -6.350 ;
        RECT 68.780 -6.530 69.680 -6.350 ;
        RECT 46.370 -7.240 46.550 -6.790 ;
        RECT 46.850 -6.860 47.030 -6.790 ;
        RECT 46.850 -7.160 47.260 -6.860 ;
        RECT 46.850 -7.240 47.030 -7.160 ;
        RECT 47.470 -7.240 47.650 -6.790 ;
        RECT 47.950 -6.860 48.130 -6.790 ;
        RECT 47.950 -7.160 48.360 -6.860 ;
        RECT 47.950 -7.240 48.130 -7.160 ;
        RECT 48.570 -7.240 48.750 -6.790 ;
        RECT 49.050 -6.860 49.230 -6.790 ;
        RECT 49.050 -7.160 49.460 -6.860 ;
        RECT 56.550 -6.900 56.850 -6.530 ;
        RECT 58.345 -6.900 58.645 -6.530 ;
        RECT 60.135 -6.900 60.435 -6.530 ;
        RECT 61.920 -6.900 62.220 -6.530 ;
        RECT 63.715 -6.900 64.015 -6.530 ;
        RECT 65.505 -6.900 65.805 -6.530 ;
        RECT 67.270 -6.900 67.570 -6.530 ;
        RECT 69.060 -6.900 69.360 -6.530 ;
        RECT 56.250 -7.080 57.150 -6.900 ;
        RECT 58.040 -7.080 58.940 -6.900 ;
        RECT 59.830 -7.080 60.730 -6.900 ;
        RECT 61.620 -7.080 62.520 -6.900 ;
        RECT 63.410 -7.080 64.310 -6.900 ;
        RECT 65.200 -7.080 66.100 -6.900 ;
        RECT 66.990 -7.080 67.890 -6.900 ;
        RECT 68.780 -7.080 69.680 -6.900 ;
        RECT 49.050 -7.240 49.230 -7.160 ;
        RECT 46.370 -8.070 46.550 -7.620 ;
        RECT 46.850 -7.695 47.030 -7.620 ;
        RECT 46.850 -7.995 47.260 -7.695 ;
        RECT 46.850 -8.070 47.030 -7.995 ;
        RECT 47.470 -8.070 47.650 -7.620 ;
        RECT 47.950 -7.695 48.130 -7.620 ;
        RECT 47.950 -7.995 48.360 -7.695 ;
        RECT 47.950 -8.070 48.130 -7.995 ;
        RECT 48.570 -8.070 48.750 -7.620 ;
        RECT 49.050 -7.695 49.230 -7.620 ;
        RECT 49.050 -7.995 49.460 -7.695 ;
        RECT 49.050 -8.070 49.230 -7.995 ;
        RECT 97.595 -8.105 98.025 -6.105 ;
        RECT 136.335 -8.105 136.895 -6.105 ;
        RECT 175.205 -8.105 175.635 -6.105 ;
        RECT 46.370 -8.900 46.550 -8.450 ;
        RECT 46.850 -8.525 47.030 -8.450 ;
        RECT 46.850 -8.825 47.260 -8.525 ;
        RECT 46.850 -8.900 47.030 -8.825 ;
        RECT 47.470 -8.900 47.650 -8.450 ;
        RECT 47.950 -8.525 48.130 -8.450 ;
        RECT 47.950 -8.825 48.360 -8.525 ;
        RECT 47.950 -8.900 48.130 -8.825 ;
        RECT 48.570 -8.900 48.750 -8.450 ;
        RECT 49.050 -8.525 49.230 -8.450 ;
        RECT 56.250 -8.460 57.150 -8.280 ;
        RECT 58.040 -8.460 58.940 -8.280 ;
        RECT 59.830 -8.460 60.730 -8.280 ;
        RECT 61.620 -8.460 62.520 -8.280 ;
        RECT 63.410 -8.460 64.310 -8.280 ;
        RECT 65.200 -8.460 66.100 -8.280 ;
        RECT 66.990 -8.460 67.890 -8.280 ;
        RECT 68.780 -8.460 69.680 -8.280 ;
        RECT 49.050 -8.825 49.460 -8.525 ;
        RECT 49.050 -8.900 49.230 -8.825 ;
        RECT 59.830 -9.010 60.730 -8.830 ;
        RECT 61.620 -9.010 62.520 -8.830 ;
        RECT 63.410 -9.010 64.310 -8.830 ;
        RECT 65.200 -9.010 66.100 -8.830 ;
        RECT 47.470 -10.240 47.650 -9.790 ;
        RECT 47.950 -9.870 48.130 -9.790 ;
        RECT 47.950 -10.170 48.360 -9.870 ;
        RECT 47.950 -10.240 48.130 -10.170 ;
        RECT 59.830 -10.390 60.730 -10.210 ;
        RECT 61.620 -10.390 62.520 -10.210 ;
        RECT 63.410 -10.390 64.310 -10.210 ;
        RECT 65.200 -10.390 66.100 -10.210 ;
        RECT 60.135 -10.760 60.435 -10.390 ;
        RECT 61.920 -10.760 62.220 -10.390 ;
        RECT 63.715 -10.760 64.015 -10.390 ;
        RECT 65.505 -10.760 65.805 -10.390 ;
        RECT 56.250 -10.940 57.150 -10.760 ;
        RECT 58.040 -10.940 58.940 -10.760 ;
        RECT 59.830 -10.940 60.730 -10.760 ;
        RECT 61.620 -10.940 62.520 -10.760 ;
        RECT 63.410 -10.940 64.310 -10.760 ;
        RECT 65.200 -10.940 66.100 -10.760 ;
        RECT 66.990 -10.940 67.890 -10.760 ;
        RECT 68.780 -10.940 69.680 -10.760 ;
        RECT 97.595 -11.520 98.025 -9.520 ;
        RECT 136.335 -11.520 136.895 -9.520 ;
        RECT 175.205 -11.520 175.635 -9.520 ;
        RECT 56.250 -12.320 57.150 -12.140 ;
        RECT 58.040 -12.320 58.940 -12.140 ;
        RECT 59.830 -12.320 60.730 -12.140 ;
        RECT 61.620 -12.320 62.520 -12.140 ;
        RECT 63.410 -12.320 64.310 -12.140 ;
        RECT 65.200 -12.320 66.100 -12.140 ;
        RECT 66.990 -12.320 67.890 -12.140 ;
        RECT 68.780 -12.320 69.680 -12.140 ;
        RECT 56.550 -12.690 56.850 -12.320 ;
        RECT 58.345 -12.690 58.645 -12.320 ;
        RECT 60.135 -12.690 60.435 -12.320 ;
        RECT 61.920 -12.690 62.220 -12.320 ;
        RECT 63.715 -12.690 64.015 -12.320 ;
        RECT 65.505 -12.690 65.805 -12.320 ;
        RECT 67.270 -12.690 67.570 -12.320 ;
        RECT 69.060 -12.690 69.360 -12.320 ;
        RECT 56.250 -12.870 57.150 -12.690 ;
        RECT 58.040 -12.870 58.940 -12.690 ;
        RECT 59.830 -12.870 60.730 -12.690 ;
        RECT 61.620 -12.870 62.520 -12.690 ;
        RECT 63.410 -12.870 64.310 -12.690 ;
        RECT 65.200 -12.870 66.100 -12.690 ;
        RECT 66.990 -12.870 67.890 -12.690 ;
        RECT 68.780 -12.870 69.680 -12.690 ;
        RECT 97.595 -13.720 98.025 -11.720 ;
        RECT 136.335 -13.720 136.895 -11.720 ;
        RECT 175.205 -13.720 175.635 -11.720 ;
        RECT 56.250 -14.250 57.150 -14.070 ;
        RECT 58.040 -14.250 58.940 -14.070 ;
        RECT 59.830 -14.250 60.730 -14.070 ;
        RECT 61.620 -14.250 62.520 -14.070 ;
        RECT 63.410 -14.250 64.310 -14.070 ;
        RECT 65.200 -14.250 66.100 -14.070 ;
        RECT 66.990 -14.250 67.890 -14.070 ;
        RECT 68.780 -14.250 69.680 -14.070 ;
        RECT 46.290 -14.860 46.590 -14.630 ;
        RECT 47.640 -14.860 47.940 -14.630 ;
        RECT 48.480 -14.860 48.780 -14.630 ;
        RECT 49.830 -14.860 50.130 -14.630 ;
        RECT 45.400 -15.040 45.800 -14.860 ;
        RECT 46.240 -15.040 46.640 -14.860 ;
        RECT 47.590 -15.040 47.990 -14.860 ;
        RECT 48.430 -15.040 48.830 -14.860 ;
        RECT 49.780 -15.040 50.180 -14.860 ;
        RECT 50.620 -15.040 51.020 -14.860 ;
        RECT 45.400 -15.370 45.800 -15.190 ;
        RECT 46.240 -15.370 46.640 -15.190 ;
        RECT 47.590 -15.370 47.990 -15.190 ;
        RECT 48.430 -15.370 48.830 -15.190 ;
        RECT 49.780 -15.370 50.180 -15.190 ;
        RECT 50.620 -15.370 51.020 -15.190 ;
        RECT 45.450 -15.670 45.750 -15.370 ;
        RECT 50.670 -15.670 50.970 -15.370 ;
        RECT 97.595 -15.920 98.025 -13.920 ;
        RECT 136.335 -15.920 136.895 -13.920 ;
        RECT 175.205 -15.920 175.635 -13.920 ;
        RECT 75.095 -16.330 75.995 -16.150 ;
        RECT 76.375 -16.330 77.275 -16.150 ;
        RECT 77.655 -16.330 78.555 -16.150 ;
        RECT 78.935 -16.330 79.835 -16.150 ;
        RECT 85.415 -17.250 87.415 -16.820 ;
        RECT 87.615 -17.250 89.615 -16.820 ;
        RECT 89.815 -17.250 91.815 -16.820 ;
        RECT 92.015 -17.250 94.015 -16.820 ;
        RECT 94.215 -17.250 96.215 -16.820 ;
        RECT 97.595 -18.120 98.025 -16.120 ;
        RECT 136.335 -18.120 136.895 -16.120 ;
        RECT 175.205 -18.120 175.635 -16.120 ;
        RECT 72.210 -18.880 74.210 -18.450 ;
        RECT 74.410 -18.880 76.410 -18.450 ;
        RECT 76.615 -18.880 78.615 -18.450 ;
        RECT 78.815 -18.880 80.815 -18.450 ;
        RECT 81.015 -18.880 83.015 -18.450 ;
        RECT 83.215 -18.880 85.215 -18.450 ;
        RECT 85.415 -18.880 87.415 -18.450 ;
        RECT 87.615 -18.880 89.615 -18.450 ;
        RECT 89.815 -18.880 91.815 -18.450 ;
        RECT 92.015 -18.880 94.015 -18.450 ;
        RECT 94.215 -18.880 96.215 -18.450 ;
        RECT 97.595 -20.325 98.025 -18.325 ;
        RECT 136.335 -20.325 136.895 -18.325 ;
        RECT 175.205 -20.325 175.635 -18.325 ;
        RECT 97.595 -22.525 98.025 -20.525 ;
        RECT 136.335 -22.525 136.895 -20.525 ;
        RECT 175.205 -22.525 175.635 -20.525 ;
        RECT 97.595 -24.725 98.025 -22.725 ;
        RECT 136.335 -24.725 136.895 -22.725 ;
        RECT 175.205 -24.725 175.635 -22.725 ;
        RECT 97.595 -26.925 98.025 -24.925 ;
        RECT 136.335 -26.925 136.895 -24.925 ;
        RECT 175.205 -26.925 175.635 -24.925 ;
        RECT 97.595 -29.125 98.025 -27.125 ;
        RECT 136.335 -29.125 136.895 -27.125 ;
        RECT 175.205 -29.125 175.635 -27.125 ;
        RECT 97.595 -31.325 98.025 -29.325 ;
        RECT 136.335 -31.325 136.895 -29.325 ;
        RECT 175.205 -31.325 175.635 -29.325 ;
        RECT 97.595 -33.525 98.025 -31.525 ;
        RECT 136.335 -33.525 136.895 -31.525 ;
        RECT 175.205 -33.525 175.635 -31.525 ;
        RECT 97.595 -35.725 98.025 -33.725 ;
        RECT 136.335 -35.725 136.895 -33.725 ;
        RECT 175.205 -35.725 175.635 -33.725 ;
        RECT 97.595 -37.925 98.025 -35.925 ;
        RECT 136.335 -37.925 136.895 -35.925 ;
        RECT 175.205 -37.925 175.635 -35.925 ;
        RECT 97.595 -40.125 98.025 -38.125 ;
        RECT 136.335 -40.125 136.895 -38.125 ;
        RECT 175.205 -40.125 175.635 -38.125 ;
        RECT 97.595 -42.325 98.025 -40.325 ;
        RECT 136.335 -42.325 136.895 -40.325 ;
        RECT 175.205 -42.325 175.635 -40.325 ;
        RECT 72.210 -44.310 74.210 -43.880 ;
        RECT 74.410 -44.310 76.410 -43.880 ;
        RECT 76.615 -44.310 78.615 -43.880 ;
        RECT 78.815 -44.310 80.815 -43.880 ;
        RECT 81.015 -44.310 83.015 -43.880 ;
        RECT 83.215 -44.310 85.215 -43.880 ;
        RECT 85.415 -44.310 87.415 -43.880 ;
        RECT 87.615 -44.310 89.615 -43.880 ;
        RECT 89.815 -44.310 91.815 -43.880 ;
        RECT 92.015 -44.310 94.015 -43.880 ;
        RECT 94.215 -44.310 96.215 -43.880 ;
        RECT 136.335 -44.525 136.895 -42.525 ;
        RECT 175.205 -44.525 175.635 -42.525 ;
      LAYER Metal1 ;
        RECT 87.635 8.310 91.795 8.610 ;
        RECT 92.035 8.310 96.195 8.610 ;
        RECT 136.465 7.315 136.765 9.275 ;
        RECT 59.405 6.635 60.005 6.795 ;
        RECT 75.220 6.730 75.920 6.940 ;
        RECT 76.500 6.730 77.200 6.940 ;
        RECT 77.770 6.730 78.470 6.940 ;
        RECT 79.055 6.730 79.755 6.940 ;
        RECT 80.325 6.730 81.025 6.940 ;
        RECT 50.700 5.780 50.910 6.480 ;
        RECT 52.380 5.995 52.590 6.480 ;
        RECT 59.845 6.455 60.005 6.635 ;
        RECT 51.095 5.835 53.875 5.995 ;
        RECT 52.380 5.780 52.590 5.835 ;
        RECT 50.725 5.570 50.885 5.780 ;
        RECT 54.085 5.570 54.245 6.435 ;
        RECT 59.845 5.755 60.055 6.455 ;
        RECT 50.725 5.410 54.245 5.570 ;
        RECT 64.820 5.340 64.980 6.485 ;
        RECT 67.355 5.810 67.565 6.485 ;
        RECT 69.915 5.920 70.125 6.620 ;
        RECT 65.195 5.600 65.895 5.810 ;
        RECT 66.470 5.600 68.440 5.810 ;
        RECT 69.015 5.600 69.715 5.810 ;
        RECT 69.940 5.340 70.100 5.920 ;
        RECT 64.820 5.180 70.100 5.340 ;
        RECT 62.100 3.660 72.800 3.960 ;
        RECT 57.575 2.635 58.275 2.845 ;
        RECT 58.455 2.155 58.755 2.455 ;
        RECT 54.245 1.710 54.545 2.010 ;
        RECT 57.575 1.755 58.275 1.965 ;
        RECT 47.455 1.330 47.950 1.540 ;
        RECT 47.650 1.300 47.950 1.330 ;
        RECT 54.720 1.470 54.880 1.475 ;
        RECT 48.070 0.820 48.380 1.120 ;
        RECT 54.720 0.770 54.930 1.470 ;
        RECT 47.455 0.470 47.950 0.680 ;
        RECT 48.105 0.120 48.315 0.375 ;
        RECT 46.550 -0.040 49.390 0.120 ;
        RECT 47.030 -0.500 47.190 -0.040 ;
        RECT 48.105 -0.325 48.315 -0.040 ;
        RECT 48.130 -0.500 48.290 -0.325 ;
        RECT 49.230 -0.500 49.390 -0.040 ;
        RECT 62.100 -0.290 62.400 3.660 ;
        RECT 63.440 3.100 64.040 3.660 ;
        RECT 64.810 3.305 70.090 3.465 ;
        RECT 63.020 2.940 64.460 3.100 ;
        RECT 63.020 0.510 63.180 2.940 ;
        RECT 64.300 0.510 64.460 2.940 ;
        RECT 64.810 0.510 64.970 3.305 ;
        RECT 66.090 2.380 66.250 2.760 ;
        RECT 67.370 2.380 67.530 2.760 ;
        RECT 65.960 0.860 66.250 2.380 ;
        RECT 67.345 0.860 67.555 2.380 ;
        RECT 65.180 0.145 65.880 0.355 ;
        RECT 66.090 0.295 66.250 0.860 ;
        RECT 67.370 0.510 67.530 0.860 ;
        RECT 68.650 0.295 68.810 2.760 ;
        RECT 69.930 2.380 70.090 3.305 ;
        RECT 70.860 3.100 71.460 3.660 ;
        RECT 70.440 2.940 71.880 3.100 ;
        RECT 69.915 0.860 70.125 2.380 ;
        RECT 69.930 0.510 70.090 0.860 ;
        RECT 70.440 0.510 70.600 2.940 ;
        RECT 71.720 0.510 71.880 2.940 ;
        RECT 66.090 0.135 68.810 0.295 ;
        RECT 69.020 0.145 69.720 0.355 ;
        RECT 72.500 -0.290 72.800 3.660 ;
        RECT 76.115 2.755 76.275 6.505 ;
        RECT 78.675 2.755 78.835 6.505 ;
        RECT 81.235 2.755 81.395 6.505 ;
        RECT 97.595 2.915 97.895 7.075 ;
        RECT 136.465 5.115 136.765 7.075 ;
        RECT 175.335 5.115 175.635 9.275 ;
        RECT 136.465 2.915 136.765 4.875 ;
        RECT 76.085 0.825 76.295 2.755 ;
        RECT 78.645 0.825 78.855 2.755 ;
        RECT 81.205 0.825 81.415 2.755 ;
        RECT 62.100 -0.590 72.800 -0.290 ;
        RECT 47.030 -1.540 47.190 -1.070 ;
        RECT 48.130 -1.270 48.290 -1.070 ;
        RECT 48.105 -1.540 48.315 -1.270 ;
        RECT 49.230 -1.540 49.390 -1.070 ;
        RECT 46.550 -1.700 49.390 -1.540 ;
        RECT 47.030 -2.165 47.190 -1.700 ;
        RECT 48.105 -1.970 48.315 -1.700 ;
        RECT 48.130 -2.165 48.290 -1.970 ;
        RECT 49.230 -2.165 49.390 -1.700 ;
        RECT 47.030 -3.200 47.190 -2.740 ;
        RECT 48.130 -2.930 48.290 -2.740 ;
        RECT 48.105 -3.200 48.315 -2.930 ;
        RECT 49.230 -3.200 49.390 -2.740 ;
        RECT 76.115 -3.095 76.275 0.825 ;
        RECT 78.675 -3.095 78.835 0.825 ;
        RECT 81.235 -3.095 81.395 0.825 ;
        RECT 97.595 -1.490 97.895 2.675 ;
        RECT 136.465 0.715 136.765 2.675 ;
        RECT 175.335 0.710 175.635 4.875 ;
        RECT 136.465 -1.485 136.765 0.475 ;
        RECT 46.550 -3.360 49.390 -3.200 ;
        RECT 47.030 -3.825 47.190 -3.360 ;
        RECT 48.105 -3.630 48.315 -3.360 ;
        RECT 48.130 -3.825 48.290 -3.630 ;
        RECT 49.230 -3.825 49.390 -3.360 ;
        RECT 47.030 -4.860 47.190 -4.405 ;
        RECT 48.130 -4.545 48.290 -4.405 ;
        RECT 48.105 -4.860 48.315 -4.545 ;
        RECT 49.230 -4.860 49.390 -4.405 ;
        RECT 46.550 -5.020 49.390 -4.860 ;
        RECT 47.030 -5.485 47.190 -5.020 ;
        RECT 48.105 -5.245 48.315 -5.020 ;
        RECT 48.130 -5.485 48.290 -5.245 ;
        RECT 49.230 -5.485 49.390 -5.020 ;
        RECT 55.980 -5.195 56.140 -5.150 ;
        RECT 47.030 -6.520 47.190 -6.055 ;
        RECT 48.130 -6.245 48.290 -6.055 ;
        RECT 48.105 -6.520 48.315 -6.245 ;
        RECT 49.230 -6.520 49.390 -6.055 ;
        RECT 55.955 -6.305 56.165 -5.195 ;
        RECT 55.980 -6.350 56.140 -6.305 ;
        RECT 59.050 -6.350 59.720 -5.150 ;
        RECT 62.630 -6.350 63.300 -5.150 ;
        RECT 66.210 -6.350 66.880 -5.150 ;
        RECT 69.790 -5.195 69.950 -5.150 ;
        RECT 69.765 -6.305 69.975 -5.195 ;
        RECT 75.190 -5.925 75.890 -5.715 ;
        RECT 76.460 -5.925 77.160 -5.715 ;
        RECT 77.745 -5.925 78.445 -5.715 ;
        RECT 79.015 -5.925 79.715 -5.715 ;
        RECT 97.595 -5.885 97.895 -1.725 ;
        RECT 136.465 -3.685 136.765 -1.725 ;
        RECT 175.335 -3.685 175.635 0.475 ;
        RECT 136.465 -5.885 136.765 -3.925 ;
        RECT 69.790 -6.350 69.950 -6.305 ;
        RECT 46.550 -6.680 49.390 -6.520 ;
        RECT 47.030 -7.140 47.190 -6.680 ;
        RECT 48.105 -6.945 48.315 -6.680 ;
        RECT 48.130 -7.140 48.290 -6.945 ;
        RECT 49.230 -7.140 49.390 -6.680 ;
        RECT 56.550 -6.865 56.850 -6.565 ;
        RECT 58.345 -6.865 58.645 -6.565 ;
        RECT 60.135 -6.865 60.435 -6.565 ;
        RECT 61.920 -6.865 62.220 -6.565 ;
        RECT 63.715 -6.865 64.015 -6.565 ;
        RECT 65.505 -6.865 65.805 -6.565 ;
        RECT 67.270 -6.865 67.570 -6.565 ;
        RECT 69.060 -6.865 69.360 -6.565 ;
        RECT 55.980 -7.120 56.140 -7.080 ;
        RECT 47.030 -8.180 47.190 -7.715 ;
        RECT 48.130 -7.910 48.290 -7.715 ;
        RECT 48.105 -8.180 48.315 -7.910 ;
        RECT 49.230 -8.180 49.390 -7.715 ;
        RECT 46.550 -8.340 49.390 -8.180 ;
        RECT 55.955 -8.230 56.165 -7.120 ;
        RECT 55.980 -8.280 56.140 -8.230 ;
        RECT 59.050 -8.280 59.720 -7.080 ;
        RECT 62.630 -8.280 63.300 -7.080 ;
        RECT 66.210 -8.280 66.880 -7.080 ;
        RECT 69.790 -7.120 69.950 -7.080 ;
        RECT 69.765 -8.230 69.975 -7.120 ;
        RECT 69.790 -8.280 69.950 -8.230 ;
        RECT 97.595 -8.245 97.895 -6.125 ;
        RECT 136.465 -8.085 136.765 -6.125 ;
        RECT 175.335 -8.085 175.635 -3.925 ;
        RECT 47.030 -8.805 47.190 -8.340 ;
        RECT 48.105 -8.610 48.315 -8.340 ;
        RECT 48.130 -8.805 48.290 -8.610 ;
        RECT 49.230 -8.805 49.390 -8.340 ;
        RECT 65.305 -8.670 66.005 -8.645 ;
        RECT 59.560 -8.830 66.370 -8.670 ;
        RECT 47.455 -9.730 47.950 -9.520 ;
        RECT 48.070 -10.170 48.410 -9.870 ;
        RECT 59.560 -10.210 59.720 -8.830 ;
        RECT 65.305 -8.855 66.005 -8.830 ;
        RECT 62.630 -9.045 62.790 -9.010 ;
        RECT 63.140 -9.045 63.300 -9.010 ;
        RECT 62.630 -10.155 63.300 -9.045 ;
        RECT 62.630 -10.210 62.790 -10.155 ;
        RECT 63.140 -10.210 63.300 -10.155 ;
        RECT 66.210 -10.210 66.370 -8.830 ;
        RECT 97.090 -9.355 97.895 -8.245 ;
        RECT 47.650 -10.380 47.950 -10.350 ;
        RECT 47.455 -10.590 47.950 -10.380 ;
        RECT 60.135 -10.725 60.435 -10.425 ;
        RECT 61.920 -10.725 62.220 -10.425 ;
        RECT 63.715 -10.725 64.015 -10.425 ;
        RECT 65.505 -10.725 65.805 -10.425 ;
        RECT 55.980 -10.995 56.140 -10.940 ;
        RECT 55.955 -12.105 56.165 -10.995 ;
        RECT 55.980 -12.140 56.140 -12.105 ;
        RECT 59.050 -12.140 59.720 -10.940 ;
        RECT 62.630 -12.140 63.300 -10.940 ;
        RECT 66.210 -12.140 66.880 -10.940 ;
        RECT 69.790 -10.995 69.950 -10.940 ;
        RECT 69.765 -12.105 69.975 -10.995 ;
        RECT 97.595 -11.500 97.895 -9.355 ;
        RECT 136.465 -11.500 136.765 -9.540 ;
        RECT 69.790 -12.140 69.950 -12.105 ;
        RECT 56.550 -12.655 56.850 -12.355 ;
        RECT 58.345 -12.655 58.645 -12.355 ;
        RECT 60.135 -12.655 60.435 -12.355 ;
        RECT 61.920 -12.655 62.220 -12.355 ;
        RECT 63.715 -12.655 64.015 -12.355 ;
        RECT 65.505 -12.655 65.805 -12.355 ;
        RECT 67.270 -12.655 67.570 -12.355 ;
        RECT 69.060 -12.655 69.360 -12.355 ;
        RECT 55.980 -12.900 56.140 -12.870 ;
        RECT 43.810 -14.055 52.610 -13.755 ;
        RECT 55.955 -14.010 56.165 -12.900 ;
        RECT 43.810 -16.155 44.110 -14.055 ;
        RECT 47.455 -14.335 47.745 -14.240 ;
        RECT 46.780 -14.495 49.640 -14.335 ;
        RECT 46.780 -14.700 46.940 -14.495 ;
        RECT 46.310 -14.860 46.940 -14.700 ;
        RECT 47.660 -14.860 47.920 -14.495 ;
        RECT 48.500 -14.860 48.760 -14.495 ;
        RECT 49.480 -14.700 49.640 -14.495 ;
        RECT 49.835 -14.700 50.125 -14.675 ;
        RECT 49.480 -14.860 50.125 -14.700 ;
        RECT 45.100 -15.440 45.260 -14.985 ;
        RECT 45.940 -15.440 46.100 -14.985 ;
        RECT 46.780 -15.245 46.940 -14.860 ;
        RECT 45.100 -15.600 46.100 -15.440 ;
        RECT 45.450 -16.155 45.750 -15.600 ;
        RECT 47.290 -15.665 47.450 -14.985 ;
        RECT 48.105 -15.370 48.315 -14.860 ;
        RECT 47.860 -15.665 48.560 -15.640 ;
        RECT 48.970 -15.665 49.130 -14.985 ;
        RECT 49.480 -15.245 49.640 -14.860 ;
        RECT 49.835 -14.885 50.125 -14.860 ;
        RECT 50.320 -15.440 50.480 -14.985 ;
        RECT 51.160 -15.440 51.320 -14.985 ;
        RECT 50.320 -15.600 51.320 -15.440 ;
        RECT 47.290 -15.825 49.130 -15.665 ;
        RECT 47.860 -15.850 48.560 -15.825 ;
        RECT 50.670 -16.155 50.970 -15.600 ;
        RECT 52.310 -16.155 52.610 -14.055 ;
        RECT 55.980 -14.070 56.140 -14.010 ;
        RECT 59.050 -14.070 59.720 -12.870 ;
        RECT 62.630 -14.070 63.300 -12.870 ;
        RECT 66.210 -14.070 66.880 -12.870 ;
        RECT 69.790 -12.900 69.950 -12.870 ;
        RECT 69.765 -14.010 69.975 -12.900 ;
        RECT 69.790 -14.070 69.950 -14.010 ;
        RECT 97.595 -15.900 97.895 -11.740 ;
        RECT 136.465 -13.700 136.765 -11.740 ;
        RECT 175.335 -13.700 175.635 -9.540 ;
        RECT 136.465 -15.900 136.765 -13.940 ;
        RECT 43.810 -16.455 52.610 -16.155 ;
        RECT 85.435 -17.250 89.605 -16.950 ;
        RECT 89.835 -17.250 94.005 -16.950 ;
        RECT 72.230 -18.750 76.395 -18.450 ;
        RECT 76.635 -18.750 80.795 -18.450 ;
        RECT 81.035 -18.750 85.200 -18.450 ;
        RECT 85.435 -18.750 89.600 -18.450 ;
        RECT 89.835 -18.750 93.995 -18.450 ;
        RECT 94.235 -18.750 96.195 -16.950 ;
        RECT 97.595 -20.305 97.895 -16.140 ;
        RECT 136.465 -18.100 136.765 -16.140 ;
        RECT 175.335 -18.105 175.635 -13.940 ;
        RECT 136.465 -20.305 136.765 -18.345 ;
        RECT 97.595 -24.705 97.895 -20.540 ;
        RECT 136.465 -22.505 136.765 -20.545 ;
        RECT 175.335 -22.505 175.635 -18.340 ;
        RECT 136.465 -24.705 136.765 -22.745 ;
        RECT 97.595 -29.105 97.895 -24.940 ;
        RECT 136.465 -26.905 136.765 -24.945 ;
        RECT 175.335 -26.905 175.635 -22.740 ;
        RECT 136.465 -29.105 136.765 -27.145 ;
        RECT 97.595 -33.505 97.895 -29.345 ;
        RECT 136.465 -31.305 136.765 -29.345 ;
        RECT 175.335 -31.305 175.635 -27.145 ;
        RECT 136.465 -33.505 136.765 -31.545 ;
        RECT 97.595 -37.910 97.895 -33.745 ;
        RECT 136.465 -35.705 136.765 -33.745 ;
        RECT 175.335 -35.710 175.635 -31.545 ;
        RECT 136.465 -37.905 136.765 -35.945 ;
        RECT 97.595 -42.305 97.895 -38.145 ;
        RECT 136.465 -40.105 136.765 -38.145 ;
        RECT 175.335 -40.105 175.635 -35.945 ;
        RECT 136.465 -42.305 136.765 -40.345 ;
        RECT 72.230 -44.310 74.190 -44.010 ;
        RECT 74.430 -44.310 78.595 -44.010 ;
        RECT 78.835 -44.310 82.995 -44.010 ;
        RECT 83.235 -44.310 87.395 -44.010 ;
        RECT 87.635 -44.310 91.795 -44.010 ;
        RECT 92.035 -44.310 96.195 -44.010 ;
        RECT 136.465 -44.505 136.765 -42.545 ;
        RECT 175.335 -44.505 175.635 -40.345 ;
      LAYER Metal2 ;
        RECT 69.920 6.735 81.025 6.935 ;
        RECT 50.700 5.780 50.910 6.480 ;
        RECT 52.380 5.780 52.590 6.480 ;
        RECT 59.845 5.755 60.055 6.455 ;
        RECT 67.355 5.810 67.565 6.485 ;
        RECT 69.920 5.920 70.120 6.735 ;
        RECT 65.175 5.600 69.715 5.810 ;
        RECT 52.385 2.845 52.585 2.885 ;
        RECT 52.385 2.635 58.275 2.845 ;
        RECT 52.385 2.595 52.585 2.635 ;
        RECT 58.505 2.160 60.050 2.450 ;
        RECT 54.250 1.755 58.275 1.965 ;
        RECT 47.455 1.335 51.880 1.535 ;
        RECT 48.110 0.905 48.310 1.115 ;
        RECT 47.455 0.055 47.745 0.675 ;
        RECT 48.105 -0.125 48.315 0.905 ;
        RECT 54.725 0.770 60.050 1.470 ;
        RECT 65.965 0.860 66.165 2.380 ;
        RECT 67.350 0.860 67.550 2.380 ;
        RECT 69.920 0.860 70.120 2.380 ;
        RECT 76.090 0.825 81.410 2.755 ;
        RECT 96.825 0.350 97.115 0.480 ;
        RECT 65.180 0.150 97.125 0.350 ;
        RECT 48.105 -0.325 58.270 -0.125 ;
        RECT 65.300 -0.545 66.000 -0.335 ;
        RECT 48.105 -1.970 48.315 -1.270 ;
        RECT 69.920 -1.275 73.260 -0.985 ;
        RECT 48.105 -3.630 48.315 -2.930 ;
        RECT 48.105 -5.245 48.315 -4.545 ;
        RECT 55.915 -4.885 81.460 -4.685 ;
        RECT 48.105 -6.945 48.315 -6.245 ;
        RECT 55.960 -6.305 56.160 -5.195 ;
        RECT 59.285 -6.300 59.485 -5.190 ;
        RECT 62.865 -6.300 63.065 -5.190 ;
        RECT 66.445 -6.300 66.645 -5.190 ;
        RECT 69.770 -6.305 69.970 -5.195 ;
        RECT 75.190 -5.920 81.460 -5.720 ;
        RECT 52.875 -6.615 53.075 -6.575 ;
        RECT 52.875 -6.815 69.355 -6.615 ;
        RECT 52.875 -6.865 53.075 -6.815 ;
        RECT 47.455 -9.790 47.745 -9.240 ;
        RECT 48.105 -10.165 48.315 -7.910 ;
        RECT 55.960 -8.230 56.160 -7.120 ;
        RECT 59.285 -8.230 59.485 -7.120 ;
        RECT 62.865 -8.230 63.065 -7.120 ;
        RECT 66.445 -8.230 66.645 -7.120 ;
        RECT 69.770 -8.230 69.970 -7.120 ;
        RECT 65.305 -8.855 66.005 -8.645 ;
        RECT 47.455 -10.585 51.880 -10.385 ;
        RECT 52.875 -10.475 53.075 -10.430 ;
        RECT 62.660 -10.475 63.270 -9.045 ;
        RECT 97.095 -9.355 97.705 -8.245 ;
        RECT 52.875 -10.675 65.800 -10.475 ;
        RECT 52.875 -10.720 53.075 -10.675 ;
        RECT 55.960 -12.105 56.160 -10.995 ;
        RECT 59.285 -12.105 59.485 -10.995 ;
        RECT 62.865 -12.105 63.065 -10.995 ;
        RECT 66.445 -12.105 66.645 -10.995 ;
        RECT 69.770 -12.105 69.970 -10.995 ;
        RECT 52.875 -12.405 53.075 -12.360 ;
        RECT 52.875 -12.605 69.355 -12.405 ;
        RECT 52.875 -12.650 53.075 -12.605 ;
        RECT 52.385 -14.050 52.915 -13.760 ;
        RECT 55.960 -14.010 56.160 -12.900 ;
        RECT 59.285 -14.035 59.485 -12.925 ;
        RECT 62.865 -14.035 63.065 -12.925 ;
        RECT 66.445 -14.035 66.645 -12.925 ;
        RECT 69.770 -14.010 69.970 -12.900 ;
        RECT 47.135 -14.445 48.040 -14.245 ;
        RECT 52.875 -14.680 53.075 -14.635 ;
        RECT 48.060 -15.370 48.360 -14.860 ;
        RECT 49.835 -14.880 53.075 -14.680 ;
        RECT 52.875 -14.925 53.075 -14.880 ;
        RECT 50.705 -15.640 50.905 -15.600 ;
        RECT 47.860 -15.850 50.905 -15.640 ;
        RECT 50.705 -15.890 50.905 -15.850 ;
        RECT 51.590 -44.260 74.175 -44.060 ;
      LAYER Metal3 ;
        RECT 47.455 -14.445 47.745 0.675 ;
        RECT 48.110 0.310 48.310 0.375 ;
        RECT 48.105 -15.260 48.315 0.310 ;
        RECT 50.700 -15.815 50.910 6.480 ;
        RECT 50.705 -15.890 50.905 -15.815 ;
        RECT 51.590 -44.260 51.880 1.535 ;
        RECT 52.380 -14.050 52.590 6.480 ;
        RECT 57.575 1.760 58.275 1.960 ;
        RECT 57.975 -0.325 58.275 1.760 ;
        RECT 59.850 0.770 60.050 6.455 ;
        RECT 67.360 6.280 67.560 6.485 ;
        RECT 65.305 0.860 66.165 2.380 ;
        RECT 67.350 1.495 67.560 6.280 ;
        RECT 67.350 0.860 67.550 1.495 ;
        RECT 65.305 -0.340 66.005 0.860 ;
        RECT 65.300 -0.540 66.005 -0.340 ;
        RECT 55.915 -4.885 56.205 -4.685 ;
        RECT 59.240 -4.885 59.530 -4.685 ;
        RECT 62.820 -4.885 63.110 -4.685 ;
        RECT 52.875 -14.925 53.075 -6.575 ;
        RECT 55.960 -14.010 56.160 -4.885 ;
        RECT 59.285 -14.035 59.485 -4.885 ;
        RECT 62.865 -14.035 63.065 -4.885 ;
        RECT 65.305 -8.850 66.005 -0.540 ;
        RECT 69.920 -1.275 70.120 6.620 ;
        RECT 81.210 2.155 81.410 2.755 ;
        RECT 81.210 0.825 81.415 2.155 ;
        RECT 66.400 -4.885 66.690 -4.685 ;
        RECT 69.725 -4.885 70.015 -4.685 ;
        RECT 66.445 -14.035 66.645 -4.885 ;
        RECT 69.770 -14.010 69.970 -4.885 ;
        RECT 73.060 -16.085 73.260 -0.985 ;
        RECT 81.215 -4.685 81.415 0.825 ;
        RECT 96.825 0.415 97.115 0.480 ;
        RECT 81.170 -4.885 81.460 -4.685 ;
        RECT 81.215 -5.720 81.415 -4.885 ;
        RECT 81.170 -5.920 81.460 -5.720 ;
        RECT 72.810 -16.695 73.510 -16.085 ;
        RECT 81.215 -17.645 81.415 -5.920 ;
        RECT 96.805 -8.245 97.115 0.415 ;
        RECT 96.805 -9.355 97.705 -8.245 ;
        RECT 80.965 -18.255 81.665 -17.645 ;
      LAYER Metal4 ;
        RECT 72.810 -16.695 73.510 -16.085 ;
        RECT 80.965 -18.255 81.665 -17.645 ;
      LAYER Metal5 ;
        RECT 72.810 -16.700 73.510 -16.080 ;
        RECT 80.965 -17.815 81.665 -17.645 ;
        RECT 44.750 -18.080 81.665 -17.815 ;
        RECT 44.750 -18.415 71.770 -18.080 ;
        RECT 80.965 -18.255 81.665 -18.080 ;
        RECT 44.750 -44.235 45.350 -18.415 ;
        RECT 71.170 -44.235 71.770 -18.415 ;
        RECT 44.750 -44.835 71.770 -44.235 ;
      LAYER TopMetal1 ;
        RECT 72.340 -18.725 73.980 -15.570 ;
        RECT 45.660 -20.425 73.980 -18.725 ;
        RECT 45.660 -43.925 70.860 -20.425 ;
  END
END LDO
END LIBRARY

